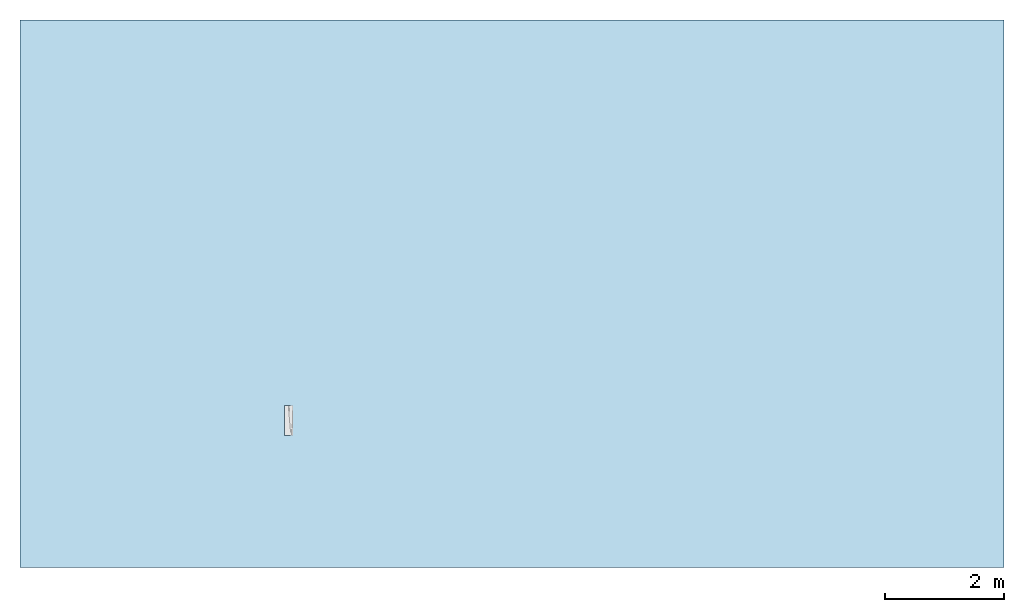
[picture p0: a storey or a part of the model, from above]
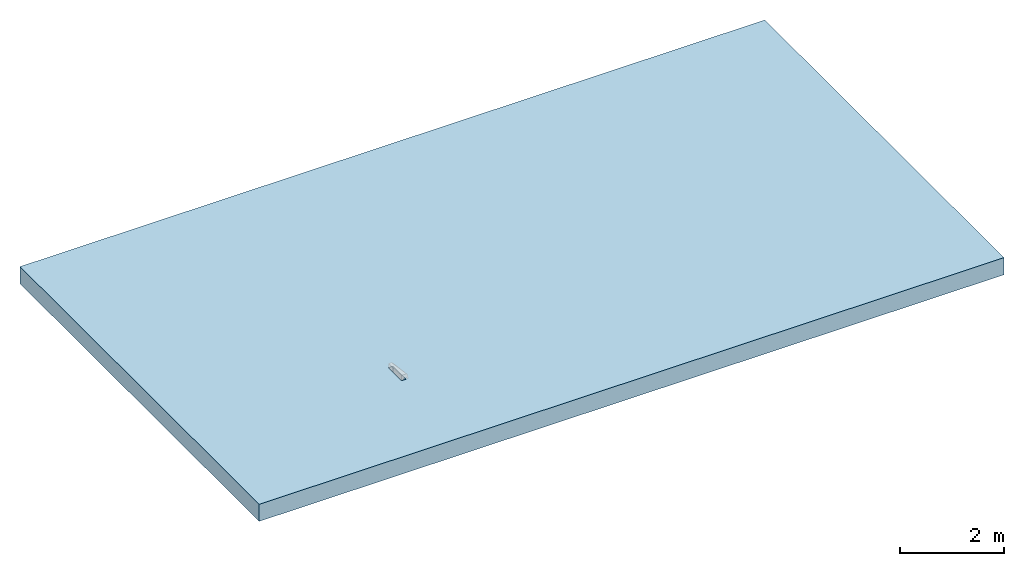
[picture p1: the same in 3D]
Properties of the parts of a building model (IFC2X3)

# File
Description: ViewDefinition [CoordinationView]
File name: 7941 - LH transition kerb - 500mm LG.ifc
Time: 2013-09-02T12:33:55
Written by: Autodesk Revit 2013
Made in: 20120221_2030(x64)

# IfcProject, Project Number
LongName: Project Name; Phase: Project Status

# IfcSite, Default
RefLatitude: 42, 21, 30, 344238; RefLongitude: -71, -3, -35, -194702; RefElevation: 0 mm

# IfcBuilding
Pset_BuildingCommon - NumberOfStoreys: 1
Other - Project Number: Project Number; Project Status: Project Status; Project Name: Project Name; Project Address: ## Street City, State Zip; Project Issue Date: Issue Date; Client Name: Owner

# IfcBuildingStorey, Level 1
LongName: Level 1; Elevation: 0 mm
Constraints - Elevation Base: 0; Elevation: 0 mm
Graphics - Color: 0; Symbol: M_Level Head - Circle: M_Level Head - Circle; Symbol at End 2 Default: yes; Line Pattern: Center; Line Weight: 1; Symbol at End 1 Default: no
Identity Data - Building Story: yes; Name: Level 1; Structural: no
Dimensions - Computation Height: 0 mm

# IfcBuildingElementProxy: 7941 - LH transition kerb - 500mm LG, Civil-Drainage-Channel-ACO-KerbDrain-SP280:7941 - LH transition kerb - 500mm LG:7941 - LH transition kerb - 500mm LG:311063
In: Level 1
Material: ACO Polymer Concrete.
Dimensions - Volume: 12693042 mm3; Void Length: 500 mm; Void Depth: -180 mm; Access hole: 100 mm; Endcap void: 230 mm; AccessDepth: 0 mm; Void Width: 150 mm
Phasing - Phase Created: New Construction
Constraints - Level: Level: Level 1; Moves With Nearby Elements: no
Pset_BuildingElementProxyCommon - Reference: 7941 - LH transition kerb - 500mm LG
Green Building Properties - Access Cover/Frame Recycled Material Content: N/A; Access Cover/Frame Recyclable: N/A; Channel Recycled Material Content: 20% minimum; Channel Recyclable: Fully recyclable; End Cap Recycled Material Content: N/A; End Cap Recyclable: N/A
Identity Data - Fax: +44 (0)1462 815895; Type Comments: ACO KerbDrain SP280 splayed LH transition unit 500mm long; Maintenance guidelines: http://www.aco.co.uk/download.php?id=120; Product Page URL: http://www.aco.co.uk/product_detail.php?id=3; Product brochure: http://www.aco.co.uk/download.php?id=120; Installation guidelines: http://www.aco.co.uk/download.php?id=120; Assembly Description: Rain Water Drainage; Manufacturer: ACO Technologies plc - ACO Water Management Division; OmniClass Number: 23.70.50.24; OmniClass Title: Rainwater Removal; e-mail Sales: customersupport@aco.co.uk; Product Code: 7941; Address: ACO Business Park, Hitchin Road, Shefford, Bedfordshire, United Kingdom SG17 5TE; Cost: 0; e-mail Technical: technical@aco.co.uk; URL: www.aco.co.uk; Assembly Code: D2040; Model: ACO KerbDrain SP280; Telephone: +44 (0)1462 816666; Price: POA - contact ACO; Model Description: Combined kerb and drainage system
Data - Connection Pipe O.D: N/A; Installation - Concrete Grade: Refer to brochure; Invert Depth: 280/255mm; ACO Hydraulic Design Software: http://www.acodesign.co.uk; Drainage Slot Intake area: N/A; Concrete Surround Volume - Load Class A 15 - D 400 - Concrete Pavement: N/A; Load Class: A 15 - D 400; Channel C.S.A: 0.02mm²; Product Dimensions: 500mm x 150mm x 305/280mm (LxWxH); Concrete Surround Volume - Load Class A 15 - D 400 - Grass or Asphalt Pavement: N/A; Drainage Slot Width: N/A; Product Weight: 24.6 Kg; Hydraulic Performance: http://www.aco.co.uk/download.php?id=120; Product Standard: BS EN 1433:2002, CE marked, Kitemarked
Materials and Finishes - Connection Pipe Material Colour: N/A; Channel Material: Vienite® Synthetic Resin Concrete; End Cap Colour: N/A; Access Cover/Frame Material: N/A; Access Cover/Frame Colour: N/A; Access Cover/Frame Finish: N/A; End Cap Material: N/A; Channel Colour: Grey; Connection Pipe Material: N/A
Construction - LH drop kerb: no; RH transition unit: no; RH inlet/outlet end cap: no; Closing end cap: no; perforated centre stone: no; Centre Stone: no; SP280-500: no; LH inlet/outlet end cap: no; Access Unit: no; LH transition unit: yes; SP280 - 1000: no; RH drop kerb: no
General - SerialNumber: 0.000000; TagNumber: 0.000000
Other - CreatedBy: www.aco.co.uk; Revision: 1

# IfcOpeningElement: Recess
In: Level 1
Dimensions - Volume: 60574500000 mm3; Thickness: 400 mm; Perimeter: 51360 mm; Area: 151470000 mm2
Constraints - Room Bounding: yes; Related to Mass: no; Height Offset From Level: 0 mm; Level: Level: Level 1
Structural - Structural: no; Enable Analytical Model: no
Phasing - Phase Created: New Construction
Analytical Properties - Absorptance: 0.1; Roughness: 1
Graphics - Coarse Scale Fill Color: 0
Materials and Finishes - Structural Material: Plant
Construction - Default Thickness: 400 mm; Function: 0

# IfcSlab: Floor:Generic Floor - 400mm, Floor:Generic Floor - 400mm:193825
In: Level 1
PredefinedType: FLOOR; Material: Plant 400 mm
Dimensions - Volume: 60574500000 mm3; Thickness: 400 mm; Perimeter: 51360 mm; Area: 151470000 mm2
Constraints - Room Bounding: yes; Related to Mass: no; Height Offset From Level: 0 mm; Level: Level: Level 1
Structural - Structural: no; Enable Analytical Model: no
Phasing - Phase Created: New Construction
Pset_SlabCommon - Reference: Generic Floor - 400mm; IsExternal: no; LoadBearing: yes
Analytical Properties - Absorptance: 0.1; Roughness: 1
Graphics - Coarse Scale Fill Color: 0
Materials and Finishes - Structural Material: Plant
Construction - Default Thickness: 400 mm; Function: 0
